VERSION 5.8 ;
BUSBITCHARS "<>" ;
DIVIDERCHAR "/" ;

UNITS
   DATABASE MICRONS 1000 ;
END UNITS

LAYER M1
   TYPE ROUTING ;
   WIDTH 1 ;
   PITCH 2 ;
   DIRECTION HORIZONTAL ;
END M1

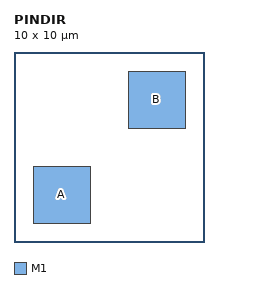
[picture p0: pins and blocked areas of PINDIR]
MACRO PINDIR
   CLASS CORE ;
   SIZE 10 BY 10 ;

   PIN A
      DIRECTION INPUT ;
      PORT
         LAYER M1 ;
         RECT 1 1 4 4 ;
      END
   END A

   PIN B
      PORT
         LAYER M1 ;
         RECT 6 6 9 9 ;
      END
   END B
END PINDIR
